VERSION 5.7 ;
  NOWIREEXTENSIONATPIN ON ;
  DIVIDERCHAR "/" ;
  BUSBITCHARS "[]" ;
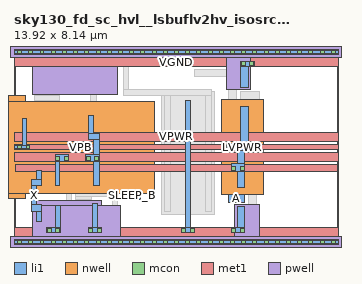
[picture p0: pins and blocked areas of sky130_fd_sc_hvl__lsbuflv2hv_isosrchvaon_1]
MACRO sky130_fd_sc_hvl__lsbuflv2hv_isosrchvaon_1
  CLASS BLOCK ;
  FOREIGN sky130_fd_sc_hvl__lsbuflv2hv_isosrchvaon_1 ;
  ORIGIN 0.000 0.000 ;
  SIZE 13.920 BY 8.140 ;
  PIN A
    ANTENNAGATEAREA 0.279000 ;
    PORT
      LAYER li1 ;
        RECT 9.205 1.685 9.895 2.015 ;
    END
  END A
  PIN SLEEP_B
    ANTENNAGATEAREA 7.125000 ;
    PORT
      LAYER li1 ;
        RECT 4.730 1.830 5.400 2.160 ;
    END
  END SLEEP_B
  PIN LVPWR
    ANTENNADIFFAREA 0.914750 ;
    PORT
      LAYER nwell ;
        RECT 8.890 2.045 10.710 6.095 ;
      LAYER li1 ;
        RECT 9.705 4.235 10.035 5.805 ;
        RECT 9.100 3.905 10.035 4.235 ;
        RECT 9.565 3.365 9.895 3.905 ;
        RECT 9.305 3.020 9.895 3.365 ;
        RECT 9.565 2.335 9.895 3.020 ;
      LAYER mcon ;
        RECT 9.335 3.080 9.505 3.250 ;
        RECT 9.695 3.080 9.865 3.250 ;
      LAYER met1 ;
        RECT 0.070 3.020 13.850 3.305 ;
    END
  END LVPWR
  PIN VGND
    USE GROUND ;
    PORT
      LAYER li1 ;
        RECT 1.760 0.625 1.990 1.565 ;
        RECT 3.360 0.625 3.590 1.655 ;
        RECT 7.340 0.625 7.570 6.055 ;
        RECT 9.565 0.625 9.895 1.515 ;
        RECT 1.400 0.395 1.990 0.625 ;
        RECT 3.175 0.395 3.765 0.625 ;
        RECT 7.155 0.395 7.745 0.625 ;
        RECT 9.305 0.395 9.895 0.625 ;
      LAYER mcon ;
        RECT 1.430 0.425 1.600 0.595 ;
        RECT 1.790 0.425 1.960 0.595 ;
        RECT 3.205 0.425 3.375 0.595 ;
        RECT 3.565 0.425 3.735 0.595 ;
        RECT 7.185 0.425 7.355 0.595 ;
        RECT 7.545 0.425 7.715 0.595 ;
        RECT 9.335 0.425 9.505 0.595 ;
        RECT 9.695 0.425 9.865 0.595 ;
      LAYER met1 ;
        RECT 0.000 0.255 13.920 0.625 ;
    END
    PORT
      LAYER li1 ;
        RECT 9.705 7.520 10.295 7.750 ;
        RECT 9.705 6.625 10.035 7.520 ;
      LAYER mcon ;
        RECT 9.735 7.550 9.905 7.720 ;
        RECT 10.095 7.550 10.265 7.720 ;
      LAYER met1 ;
        RECT 0.000 7.515 13.920 7.885 ;
    END
  END VGND
  PIN VNB
    ANTENNADIFFAREA 2.366400 ;
    PORT
      LAYER pwell ;
        RECT -0.130 7.925 14.050 8.355 ;
        RECT 0.810 6.335 4.440 7.925 ;
        RECT 9.095 6.515 10.145 7.925 ;
      LAYER li1 ;
        RECT 0.000 8.055 13.920 8.225 ;
      LAYER mcon ;
        RECT 0.155 8.055 0.325 8.225 ;
        RECT 0.635 8.055 0.805 8.225 ;
        RECT 1.115 8.055 1.285 8.225 ;
        RECT 1.595 8.055 1.765 8.225 ;
        RECT 2.075 8.055 2.245 8.225 ;
        RECT 2.555 8.055 2.725 8.225 ;
        RECT 3.035 8.055 3.205 8.225 ;
        RECT 3.515 8.055 3.685 8.225 ;
        RECT 3.995 8.055 4.165 8.225 ;
        RECT 4.475 8.055 4.645 8.225 ;
        RECT 4.955 8.055 5.125 8.225 ;
        RECT 5.435 8.055 5.605 8.225 ;
        RECT 5.915 8.055 6.085 8.225 ;
        RECT 6.395 8.055 6.565 8.225 ;
        RECT 6.875 8.055 7.045 8.225 ;
        RECT 7.355 8.055 7.525 8.225 ;
        RECT 7.835 8.055 8.005 8.225 ;
        RECT 8.315 8.055 8.485 8.225 ;
        RECT 8.795 8.055 8.965 8.225 ;
        RECT 9.275 8.055 9.445 8.225 ;
        RECT 9.755 8.055 9.925 8.225 ;
        RECT 10.235 8.055 10.405 8.225 ;
        RECT 10.715 8.055 10.885 8.225 ;
        RECT 11.195 8.055 11.365 8.225 ;
        RECT 11.675 8.055 11.845 8.225 ;
        RECT 12.155 8.055 12.325 8.225 ;
        RECT 12.635 8.055 12.805 8.225 ;
        RECT 13.115 8.055 13.285 8.225 ;
        RECT 13.595 8.055 13.765 8.225 ;
      LAYER met1 ;
        RECT 0.000 8.025 13.920 8.255 ;
    END
    PORT
      LAYER pwell ;
        RECT 0.810 1.545 3.730 1.795 ;
        RECT 0.810 0.215 4.570 1.545 ;
        RECT 9.455 0.215 10.505 1.625 ;
        RECT -0.130 -0.215 14.050 0.215 ;
      LAYER li1 ;
        RECT 0.000 -0.085 13.920 0.085 ;
      LAYER mcon ;
        RECT 0.155 -0.085 0.325 0.085 ;
        RECT 0.635 -0.085 0.805 0.085 ;
        RECT 1.115 -0.085 1.285 0.085 ;
        RECT 1.595 -0.085 1.765 0.085 ;
        RECT 2.075 -0.085 2.245 0.085 ;
        RECT 2.555 -0.085 2.725 0.085 ;
        RECT 3.035 -0.085 3.205 0.085 ;
        RECT 3.515 -0.085 3.685 0.085 ;
        RECT 3.995 -0.085 4.165 0.085 ;
        RECT 4.475 -0.085 4.645 0.085 ;
        RECT 4.955 -0.085 5.125 0.085 ;
        RECT 5.435 -0.085 5.605 0.085 ;
        RECT 5.915 -0.085 6.085 0.085 ;
        RECT 6.395 -0.085 6.565 0.085 ;
        RECT 6.875 -0.085 7.045 0.085 ;
        RECT 7.355 -0.085 7.525 0.085 ;
        RECT 7.835 -0.085 8.005 0.085 ;
        RECT 8.315 -0.085 8.485 0.085 ;
        RECT 8.795 -0.085 8.965 0.085 ;
        RECT 9.275 -0.085 9.445 0.085 ;
        RECT 9.755 -0.085 9.925 0.085 ;
        RECT 10.235 -0.085 10.405 0.085 ;
        RECT 10.715 -0.085 10.885 0.085 ;
        RECT 11.195 -0.085 11.365 0.085 ;
        RECT 11.675 -0.085 11.845 0.085 ;
        RECT 12.155 -0.085 12.325 0.085 ;
        RECT 12.635 -0.085 12.805 0.085 ;
        RECT 13.115 -0.085 13.285 0.085 ;
        RECT 13.595 -0.085 13.765 0.085 ;
      LAYER met1 ;
        RECT 0.000 -0.115 13.920 0.115 ;
    END
  END VNB
  PIN VPB
    ANTENNADIFFAREA 0.307700 ;
    PORT
      LAYER nwell ;
        RECT -0.330 6.005 0.510 6.255 ;
        RECT -0.330 2.095 6.020 6.005 ;
        RECT -0.330 1.885 0.510 2.095 ;
      LAYER li1 ;
        RECT 0.360 4.155 0.530 5.280 ;
        RECT 0.000 3.985 0.685 4.155 ;
      LAYER mcon ;
        RECT 0.155 3.985 0.325 4.155 ;
        RECT 0.515 3.985 0.685 4.155 ;
      LAYER met1 ;
        RECT 0.000 3.955 13.920 4.185 ;
    END
  END VPB
  PIN VPWR
    USE POWER ;
    PORT
      LAYER met1 ;
        RECT 0.000 4.325 13.920 4.695 ;
    END
    PORT
      LAYER li1 ;
        RECT 3.175 4.630 3.395 5.405 ;
        RECT 3.175 4.410 3.645 4.630 ;
        RECT 3.425 3.735 3.645 4.410 ;
        RECT 1.760 3.445 2.350 3.735 ;
        RECT 3.060 3.445 3.645 3.735 ;
        RECT 1.760 2.405 1.930 3.445 ;
        RECT 3.425 2.405 3.645 3.445 ;
      LAYER mcon ;
        RECT 1.790 3.505 1.960 3.675 ;
        RECT 2.150 3.505 2.320 3.675 ;
        RECT 3.090 3.505 3.260 3.675 ;
        RECT 3.450 3.505 3.620 3.675 ;
      LAYER met1 ;
        RECT 0.000 3.445 13.920 3.815 ;
    END
  END VPWR
  PIN X
    ANTENNADIFFAREA 0.397500 ;
    PORT
      LAYER li1 ;
        RECT 0.955 2.695 1.175 3.075 ;
        RECT 0.755 2.405 1.175 2.695 ;
        RECT 0.755 1.605 0.975 2.405 ;
        RECT 0.755 1.315 1.175 1.605 ;
        RECT 0.955 0.895 1.175 1.315 ;
    END
  END X
  OBS
      LAYER pwell ;
        RECT 6.320 1.195 8.590 6.455 ;
      LAYER li1 ;
        RECT 0.955 7.625 4.900 7.845 ;
        RECT 0.955 6.445 1.175 7.625 ;
        RECT 1.735 6.275 1.955 7.455 ;
        RECT 2.515 6.445 2.735 7.625 ;
        RECT 0.895 6.055 1.955 6.275 ;
        RECT 0.895 4.795 1.115 6.055 ;
        RECT 3.295 5.885 3.515 7.455 ;
        RECT 4.075 6.445 4.295 7.625 ;
        RECT 4.680 6.515 4.900 7.625 ;
        RECT 7.750 7.075 9.535 7.405 ;
        RECT 4.680 6.295 8.445 6.515 ;
        RECT 1.365 5.665 5.675 5.885 ;
        RECT 1.365 5.555 2.035 5.665 ;
        RECT 5.455 4.945 5.675 5.665 ;
        RECT 0.895 4.575 2.780 4.795 ;
        RECT 2.110 4.295 2.780 4.575 ;
        RECT 2.560 3.085 2.780 4.295 ;
        RECT 2.260 2.860 2.780 3.085 ;
        RECT 2.260 0.645 2.480 2.860 ;
        RECT 4.205 2.160 4.425 3.755 ;
        RECT 2.650 1.940 4.425 2.160 ;
        RECT 2.650 1.830 3.320 1.940 ;
        RECT 4.205 0.645 4.425 1.940 ;
        RECT 6.465 1.305 6.685 6.295 ;
        RECT 8.225 1.305 8.445 6.295 ;
        RECT 9.205 4.775 9.535 7.075 ;
        RECT 9.705 6.125 10.535 6.455 ;
        RECT 10.205 3.365 10.535 6.125 ;
        RECT 10.065 3.035 10.535 3.365 ;
        RECT 10.065 0.735 10.395 3.035 ;
  END
END sky130_fd_sc_hvl__lsbuflv2hv_isosrchvaon_1
END LIBRARY

